# BSD 3-Clause License
# 
# Copyright 2020 Lawrence T. Clark, Vinay Vashishtha, or Arizona State
# University
# 
# Redistribution and use in source and binary forms, with or without
# modification, are permitted provided that the following conditions are met:
# 
# 1. Redistributions of source code must retain the above copyright notice,
# this list of conditions and the following disclaimer.
# 
# 2. Redistributions in binary form must reproduce the above copyright
# notice, this list of conditions and the following disclaimer in the
# documentation and/or other materials provided with the distribution.
# 
# 3. Neither the name of the copyright holder nor the names of its
# contributors may be used to endorse or promote products derived from this
# software without specific prior written permission.
# 
# THIS SOFTWARE IS PROVIDED BY THE COPYRIGHT HOLDERS AND CONTRIBUTORS "AS IS"
# AND ANY EXPRESS OR IMPLIED WARRANTIES, INCLUDING, BUT NOT LIMITED TO, THE
# IMPLIED WARRANTIES OF MERCHANTABILITY AND FITNESS FOR A PARTICULAR PURPOSE
# ARE DISCLAIMED. IN NO EVENT SHALL THE COPYRIGHT HOLDER OR CONTRIBUTORS BE
# LIABLE FOR ANY DIRECT, INDIRECT, INCIDENTAL, SPECIAL, EXEMPLARY, OR
# CONSEQUENTIAL DAMAGES (INCLUDING, BUT NOT LIMITED TO, PROCUREMENT OF
# SUBSTITUTE GOODS OR SERVICES; LOSS OF USE, DATA, OR PROFITS; OR BUSINESS
# INTERRUPTION) HOWEVER CAUSED AND ON ANY THEORY OF LIABILITY, WHETHER IN
# CONTRACT, STRICT LIABILITY, OR TORT (INCLUDING NEGLIGENCE OR OTHERWISE)
# ARISING IN ANY WAY OUT OF THE USE OF THIS SOFTWARE, EVEN IF ADVISED OF THE
# POSSIBILITY OF SUCH DAMAGE.

# -----------------------------------------------------------------------------
# smic-n3 variant of the ASAP7 technology LEF.
# Author of the variant: Simone Machetti
#
# The ASAP7 standard cells draw their pins and wiring on M1 and M2 only, so
# everything up to and including V2 is ASAP7's, unchanged. From M3 up the stack
# takes the metal pitches measured on SMIC N+3 (Kirin 9030 Pro teardown), with
# widths at half the pitch and the preferred directions alternating as before:
#
#   M1, M2      36 nm   ASAP7, frozen by the cells
#   M3          44 nm   fine layer, ASAP7's M3 rules scaled by 44/36
#   M4 to M6    80 nm   classic rules, ASAP7's M8 verbatim
#   M7 to M10  128 nm   classic rules, ASAP7's M8 scaled by 1.6
#   M11        148 nm   classic rules, ASAP7's M8 scaled by 1.85
#   Pad                 ASAP7's, unused
#
# The pitches are measurements; the design rules around them are not published
# and are ASAP7's own, scaled. This file holds no thickness or material data:
# the electrical model is in setRC.tcl and rcx_patterns.rules.
# -----------------------------------------------------------------------------

VERSION 5.8 ;
BUSBITCHARS "[]" ;
DIVIDERCHAR "/" ;
CLEARANCEMEASURE EUCLIDEAN ;
USEMINSPACING OBS OFF ;

UNITS
 DATABASE MICRONS 1000 ;
END UNITS
 MANUFACTURINGGRID 0.001 ;

PROPERTYDEFINITIONS
  LAYER LEF58_TYPE STRING ;
  LAYER LEF58_PITCH STRING ;
  LAYER LEF58_GAP STRING ;
  LAYER LEF58_EOLKEEPOUT STRING ;
  LAYER LEF58_SPACING STRING ;
  LAYER LEF58_CORNERSPACING STRING ;
  LAYER LEF58_WIDTHTABLE STRING ;
  LAYER LEF58_CUTCLASS STRING ;
  LAYER LEF58_SPACINGTABLE STRING ;
  LAYER LEF58_ENCLOSURE STRING ;
  LAYER LEF58_RIGHTWAYONGRIDONLY STRING ;
  LAYER LEF58_RECTONLY STRING ;
END PROPERTYDEFINITIONS

#LAYER OVERLAP
#  TYPE OVERLAP ;
#END OVERLAP
#

LAYER LVTN
  TYPE IMPLANT ;
END LVTN

LAYER LVTP
  TYPE IMPLANT ;
END LVTP

LAYER RVTN
  TYPE IMPLANT ;
END RVTN

LAYER RVTP
  TYPE IMPLANT ;
END RVTP

LAYER SLVTN
  TYPE IMPLANT ;
END SLVTN

LAYER SLVTP
  TYPE IMPLANT ;
END SLVTP

LAYER nwell
  TYPE MASTERSLICE ;
 PROPERTY LEF58_TYPE "TYPE NWELL ;" ;
END nwell

LAYER pwell
  TYPE MASTERSLICE ;
 PROPERTY LEF58_TYPE "TYPE PWELL ;" ;
END pwell

LAYER Gate
  TYPE MASTERSLICE ;
END Gate

LAYER Active
  TYPE MASTERSLICE ;
END Active

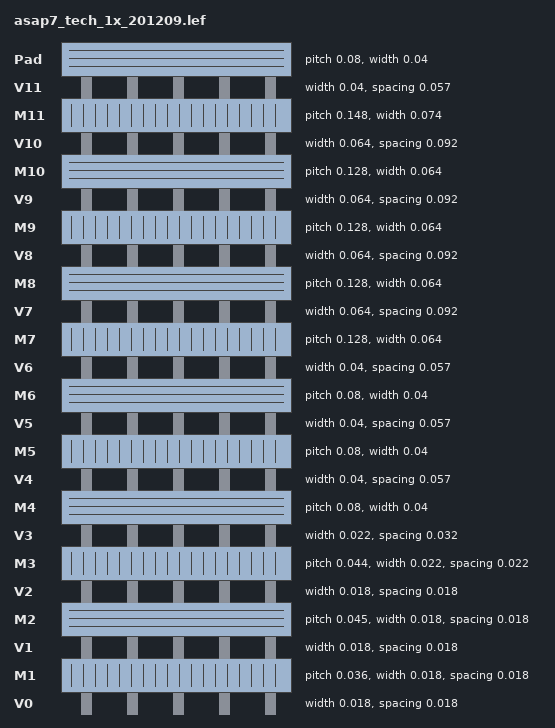
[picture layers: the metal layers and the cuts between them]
LAYER V0
  TYPE CUT ;
 SPACING 0.018 ;
 WIDTH 0.018 ;
END V0

LAYER M1
  TYPE ROUTING ;
  DIRECTION VERTICAL ;
 PITCH 0.036 ;
 WIDTH 0.018 ;
 SPACING 0.018 ;
 AREA 0.000666 ; # Min Area
                                    # we only allow landing on pins (set in router) so area should not matter
 SPACING 0.018 RANGE 0.036 1.0 ; # This rule is redundant with the SPACING rule

 PROPERTY LEF58_EOLKEEPOUT "EOLKEEPOUT 0.01825 EXTENSION 0.0 0.0 0.031 ;" ; # Tip to Tip Spacing

 PROPERTY LEF58_CORNERSPACING "CORNERSPACING CONVEXCORNER CORNERONLY 0.01 WIDTH 0.018 SPACING 0.018 ;" ;
 OFFSET 0.0 ;

END M1

LAYER V1
  TYPE CUT ;
 SPACING 0.018 ; # unlike generate, this is really spacing, not center to center.
 WIDTH 0.018 ;
END V1

LAYER M2
  TYPE ROUTING ;
  DIRECTION HORIZONTAL ;
 WIDTH 0.018 ; # Min Width
 SPACING 0.018 ; # Min Spacing

 OFFSET -0.27 ;

  #  MINSIZE is set so that the minimum lenght of a segment is 36nm. At the proper rule size of
  #  31nm, the lines can't be minimum space. This causes DRCs (like crazy). Same for M3
  #  MINSIZE 0.112 0.072 ; 
  # area is adjusted to match this (Nanoroute requires both AREA and MINSIZE)

 AREA 0.000666 ;
 MINSIZE 0.037 0.018 ;

 PITCH 0.045 0.036 ;

  # this enforces the correct routing tracks on M2 with wide M2 power rails

 PROPERTY LEF58_PITCH "
 PITCH 0.036 FIRSTLASTPITCH 0.045
   ;
 " ;

  # this checks for distance in any direction so is not correct
  # 0.070 is to avoid conflicts with the adjacent lines. This should be caught by CORNERSPACING below
  #   SPACING 0.124 ENDOFLINE 0.1 WITHIN 0.070 ;

 PROPERTY LEF58_SPACING
 " SPACING 0.018 ENDOFLINE 0.025 WITHIN 0.02 ENDTOEND 0.031
 PARALLELEDGE 0.025 WITHIN 0.02 ; " ;

 PROPERTY LEF58_EOLKEEPOUT "
 EOLKEEPOUT 0.025 EXTENSION 0.0 0.0125 0.031 CORNERONLY ;
 " ;

 PROPERTY LEF58_CORNERSPACING "
 CORNERSPACING CONVEXCORNER WIDTH 0.0 SPACING 0.02 ;
 " ; # CORNER to CORNER SPACING Rule

  # Originally no width table for M2 since it is the follow rails. 
  # They can be 1x or 2x (2x causes DRCs on SAV V1). However, this seems to allow a double width M2
  # on vias, which violates. Thus, this is added. Note that wide power follow rails will violate.

 PROPERTY LEF58_WIDTHTABLE "
 WIDTHTABLE 0.018 0.09 0.162 0.234 0.306 0.378 ;
 " ;

 PROPERTY LEF58_RIGHTWAYONGRIDONLY "
      RIGHTWAYONGRIDONLY ;
 " ;

 PROPERTY LEF58_RECTONLY "
      RECTONLY ;
 " ;

END M2

LAYER V2
  TYPE CUT ;
 SPACING 0.018 ;
 WIDTH 0.018 ;
END V2

LAYER M3
  TYPE ROUTING ;
  DIRECTION VERTICAL ;
 PITCH 0.044 ;
 OFFSET 0.0 ;
 WIDTH 0.022 ; # Min Width
 SPACING 0.022 ; # Min Spacing

  # smic-n3: the last finely patterned layer. It keeps ASAP7's M3 rule set, with
  # every length scaled by the pitch ratio 44/36 and rounded to the 1 nm grid.
  # MINSIZE keeps the minimum segment one nanometre above the pitch, as on M2.

 AREA 0.00099 ;
 MINSIZE 0.045 0.022 ;

 PROPERTY LEF58_SPACING
 " SPACING 0.022 ENDOFLINE 0.031 WITHIN 0.015 ENDTOEND 0.038
 PARALLELEDGE 0.031 WITHIN 0.024 ; " ;

 PROPERTY LEF58_EOLKEEPOUT "
 EOLKEEPOUT 0.031 EXTENSION 0.0 0.015 0.038 CORNERONLY ;
 " ;

 PROPERTY LEF58_CORNERSPACING "
 CORNERSPACING CONVEXCORNER WIDTH 0.0 SPACING 0.024
   ;
 " ; # CORNER to CORNER SPACING Rule

  # special route widths are integer numbers of tracks: 1, 5, 9, 13... min widths

 PROPERTY LEF58_WIDTHTABLE
 " WIDTHTABLE 0.022 0.11 0.198 0.286 0.374 0.462 ; " ;

 PROPERTY LEF58_RIGHTWAYONGRIDONLY "
      RIGHTWAYONGRIDONLY ;
 " ;

 PROPERTY LEF58_RECTONLY "
      RECTONLY ;
 " ;

END M3

# smic-n3: from here up every layer is coarse and single-patterned, and carries
# the classic rule set of ASAP7's M8: pitch, width, minimum area, a spacing table
# by parallel run length, minimum cut, maximum width and minimum step. The 80 nm
# layers (M4 to M6) are ASAP7's M8 verbatim; the 128 nm layers (M7 to M10) and
# the 148 nm layer (M11) are the same block with every length scaled by the
# width ratio (1.6 and 1.85) and the area by its square. Cut layers are square
# at the width of the narrower neighbour, spaced as ASAP7 spaces V7 and V8
# (1.43 x the cut).

LAYER V3
  TYPE CUT ;
 SPACING 0.032 ;
 WIDTH 0.022 ;
END V3

LAYER M4
  TYPE ROUTING ;
  DIRECTION HORIZONTAL ;
 PITCH 0.08 0.08 ;
 WIDTH 0.04 ;
 AREA 0.00752 ;

  SPACINGTABLE
 PARALLELRUNLENGTH 0.0 0.39975 1.19975 1.79975
 WIDTH 0.0 0.04 0.04 0.04 0.04
 WIDTH 0.05975 0.04 0.04 0.04 0.04
 WIDTH 0.07975 0.04 0.04 0.04 0.04
 WIDTH 0.11975 0.04 0.04 0.04 0.04
 WIDTH 0.49975 0.04 0.04 0.04 0.5
 WIDTH 0.99975 0.04 0.04 0.04 1.0 ;

 MINIMUMCUT 2 WIDTH 1.805 WITHIN 1.705 FROMBELOW ;
 MINIMUMCUT 2 WIDTH 1.805 WITHIN 1.705 FROMABOVE ;
 MAXWIDTH 2.0 ;
 MINSTEP 0.04 STEP ;
END M4

LAYER V4
  TYPE CUT ;
 SPACING 0.057 ;
 WIDTH 0.04 ;
END V4

LAYER M5
  TYPE ROUTING ;
  DIRECTION VERTICAL ;
 PITCH 0.08 0.08 ;
 WIDTH 0.04 ;
 AREA 0.00752 ;

  SPACINGTABLE
 PARALLELRUNLENGTH 0.0 0.39975 1.19975 1.79975
 WIDTH 0.0 0.04 0.04 0.04 0.04
 WIDTH 0.05975 0.04 0.04 0.04 0.04
 WIDTH 0.07975 0.04 0.04 0.04 0.04
 WIDTH 0.11975 0.04 0.04 0.04 0.04
 WIDTH 0.49975 0.04 0.04 0.04 0.5
 WIDTH 0.99975 0.04 0.04 0.04 1.0 ;

 MINIMUMCUT 2 WIDTH 1.805 WITHIN 1.705 FROMBELOW ;
 MINIMUMCUT 2 WIDTH 1.805 WITHIN 1.705 FROMABOVE ;
 MAXWIDTH 2.0 ;
 MINSTEP 0.04 STEP ;
END M5

LAYER V5
  TYPE CUT ;
 SPACING 0.057 ;
 WIDTH 0.04 ;
END V5

LAYER M6
  TYPE ROUTING ;
  DIRECTION HORIZONTAL ;
 PITCH 0.08 0.08 ;
 WIDTH 0.04 ;
 AREA 0.00752 ;

  SPACINGTABLE
 PARALLELRUNLENGTH 0.0 0.39975 1.19975 1.79975
 WIDTH 0.0 0.04 0.04 0.04 0.04
 WIDTH 0.05975 0.04 0.04 0.04 0.04
 WIDTH 0.07975 0.04 0.04 0.04 0.04
 WIDTH 0.11975 0.04 0.04 0.04 0.04
 WIDTH 0.49975 0.04 0.04 0.04 0.5
 WIDTH 0.99975 0.04 0.04 0.04 1.0 ;

 MINIMUMCUT 2 WIDTH 1.805 WITHIN 1.705 FROMBELOW ;
 MINIMUMCUT 2 WIDTH 1.805 WITHIN 1.705 FROMABOVE ;
 MAXWIDTH 2.0 ;
 MINSTEP 0.04 STEP ;
END M6

LAYER V6
  TYPE CUT ;
 SPACING 0.057 ;
 WIDTH 0.04 ;
END V6

LAYER M7
  TYPE ROUTING ;
  DIRECTION VERTICAL ;
 PITCH 0.128 0.128 ;
 WIDTH 0.064 ;
 AREA 0.01925 ;

  SPACINGTABLE
 PARALLELRUNLENGTH 0.0 0.63975 1.91975 2.87975
 WIDTH 0.0 0.064 0.064 0.064 0.064
 WIDTH 0.09575 0.064 0.064 0.064 0.064
 WIDTH 0.12775 0.064 0.064 0.064 0.064
 WIDTH 0.19175 0.064 0.064 0.064 0.064
 WIDTH 0.79975 0.064 0.064 0.064 0.8
 WIDTH 1.59975 0.064 0.064 0.064 1.6 ;

 MINIMUMCUT 2 WIDTH 2.888 WITHIN 2.728 FROMBELOW ;
 MINIMUMCUT 2 WIDTH 2.888 WITHIN 2.728 FROMABOVE ;
 MAXWIDTH 3.2 ;
 MINSTEP 0.064 STEP ;
END M7

LAYER V7
  TYPE CUT ;
 SPACING 0.092 ;
 WIDTH 0.064 ;
END V7

LAYER M8
  TYPE ROUTING ;
  DIRECTION HORIZONTAL ;
 PITCH 0.128 0.128 ;
 WIDTH 0.064 ;
 AREA 0.01925 ;

  SPACINGTABLE
 PARALLELRUNLENGTH 0.0 0.63975 1.91975 2.87975
 WIDTH 0.0 0.064 0.064 0.064 0.064
 WIDTH 0.09575 0.064 0.064 0.064 0.064
 WIDTH 0.12775 0.064 0.064 0.064 0.064
 WIDTH 0.19175 0.064 0.064 0.064 0.064
 WIDTH 0.79975 0.064 0.064 0.064 0.8
 WIDTH 1.59975 0.064 0.064 0.064 1.6 ;

 MINIMUMCUT 2 WIDTH 2.888 WITHIN 2.728 FROMBELOW ;
 MINIMUMCUT 2 WIDTH 2.888 WITHIN 2.728 FROMABOVE ;
 MAXWIDTH 3.2 ;
 MINSTEP 0.064 STEP ;
END M8

LAYER V8
  TYPE CUT ;
 SPACING 0.092 ;
 WIDTH 0.064 ;
END V8

LAYER M9
  TYPE ROUTING ;
  DIRECTION VERTICAL ;
 PITCH 0.128 0.128 ;
 WIDTH 0.064 ;
 AREA 0.01925 ;

  SPACINGTABLE
 PARALLELRUNLENGTH 0.0 0.63975 1.91975 2.87975
 WIDTH 0.0 0.064 0.064 0.064 0.064
 WIDTH 0.09575 0.064 0.064 0.064 0.064
 WIDTH 0.12775 0.064 0.064 0.064 0.064
 WIDTH 0.19175 0.064 0.064 0.064 0.064
 WIDTH 0.79975 0.064 0.064 0.064 0.8
 WIDTH 1.59975 0.064 0.064 0.064 1.6 ;

 MINIMUMCUT 2 WIDTH 2.888 WITHIN 2.728 FROMBELOW ;
 MINIMUMCUT 2 WIDTH 2.888 WITHIN 2.728 FROMABOVE ;
 MAXWIDTH 3.2 ;
 MINSTEP 0.064 STEP ;
END M9

LAYER V9
  TYPE CUT ;
 SPACING 0.092 ;
 WIDTH 0.064 ;
END V9

LAYER M10
  TYPE ROUTING ;
  DIRECTION HORIZONTAL ;
 PITCH 0.128 0.128 ;
 WIDTH 0.064 ;
 AREA 0.01925 ;

  SPACINGTABLE
 PARALLELRUNLENGTH 0.0 0.63975 1.91975 2.87975
 WIDTH 0.0 0.064 0.064 0.064 0.064
 WIDTH 0.09575 0.064 0.064 0.064 0.064
 WIDTH 0.12775 0.064 0.064 0.064 0.064
 WIDTH 0.19175 0.064 0.064 0.064 0.064
 WIDTH 0.79975 0.064 0.064 0.064 0.8
 WIDTH 1.59975 0.064 0.064 0.064 1.6 ;

 MINIMUMCUT 2 WIDTH 2.888 WITHIN 2.728 FROMBELOW ;
 MINIMUMCUT 2 WIDTH 2.888 WITHIN 2.728 FROMABOVE ;
 MAXWIDTH 3.2 ;
 MINSTEP 0.064 STEP ;
END M10

LAYER V10
  TYPE CUT ;
 SPACING 0.092 ;
 WIDTH 0.064 ;
END V10

LAYER M11
  TYPE ROUTING ;
  DIRECTION VERTICAL ;
 PITCH 0.148 0.148 ;
 WIDTH 0.074 ;
 AREA 0.02574 ;

  SPACINGTABLE
 PARALLELRUNLENGTH 0.0 0.73975 2.21975 3.32975
 WIDTH 0.0 0.074 0.074 0.074 0.074
 WIDTH 0.11075 0.074 0.074 0.074 0.074
 WIDTH 0.14775 0.074 0.074 0.074 0.074
 WIDTH 0.22175 0.074 0.074 0.074 0.074
 WIDTH 0.92475 0.074 0.074 0.074 0.925
 WIDTH 1.84975 0.074 0.074 0.074 1.85 ;

 MINIMUMCUT 2 WIDTH 3.339 WITHIN 3.154 FROMBELOW ;
 MINIMUMCUT 2 WIDTH 3.339 WITHIN 3.154 FROMABOVE ;
 MAXWIDTH 3.7 ;
 MINSTEP 0.074 STEP ;
END M11

# smic-n3: the Pad layer and its cut are ASAP7's, moved above M11. Nothing in the
# flow routes on them. SMIC's two package-scale layers above M11 are left out.

LAYER V11
  TYPE CUT ;
 SPACING 0.057 ;
 WIDTH 0.04 ;
END V11

LAYER Pad
  TYPE ROUTING ;
  DIRECTION HORIZONTAL ;
 PITCH 0.08 0.08 ;
 WIDTH 0.04 ;
  SPACINGTABLE
 PARALLELRUNLENGTH 0.0 11.99975
 WIDTH 0.0 2.0 2.0
 WIDTH 11.99975 2.0 3.0 ;
 MINIMUMCUT 1 WIDTH 0.04 WITHIN 1.705 FROMBELOW ;
 MINIMUMCUT 1 WIDTH 0.36 WITHIN 1.705 FROMBELOW ;
 MINIMUMCUT 2 WIDTH 1.805 WITHIN 1.705 FROMBELOW ;
 MINIMUMDENSITY 20.0 ;
 MAXIMUMDENSITY 80.0 ;
 DENSITYCHECKWINDOW 100.0 100.0 ;
 DENSITYCHECKSTEP 50.0 ;
END Pad

# vias
#
# smic-n3: one fixed via per adjacent pair, used as the router's default cut.
# On the coarse layers the metal is a square of the wire width around the cut,
# as in ASAP7's VIA89. On M3 the enclosure runs 5 nm past the cut along the wire,
# as in ASAP7's VIA23 and VIA34.

VIA VIA11Pad Default
  LAYER M11 ;
 RECT -0.05 -0.05 0.05 0.05 ;
  LAYER Pad ;
 RECT -0.05 -0.05 0.05 0.05 ;
  LAYER V11 ;
 RECT -0.05 -0.05 0.05 0.05 ;
END VIA11Pad

VIA VIA1011 Default
  LAYER M10 ;
 RECT -0.032 -0.032 0.032 0.032 ;
  LAYER M11 ;
 RECT -0.037 -0.037 0.037 0.037 ;
  LAYER V10 ;
 RECT -0.032 -0.032 0.032 0.032 ;
END VIA1011

VIA VIA910 Default
  LAYER M9 ;
 RECT -0.032 -0.032 0.032 0.032 ;
  LAYER M10 ;
 RECT -0.032 -0.032 0.032 0.032 ;
  LAYER V9 ;
 RECT -0.032 -0.032 0.032 0.032 ;
END VIA910

VIA VIA89 Default
  LAYER M8 ;
 RECT -0.032 -0.032 0.032 0.032 ;
  LAYER M9 ;
 RECT -0.032 -0.032 0.032 0.032 ;
  LAYER V8 ;
 RECT -0.032 -0.032 0.032 0.032 ;
END VIA89

VIA VIA78 Default
  LAYER M7 ;
 RECT -0.032 -0.032 0.032 0.032 ;
  LAYER M8 ;
 RECT -0.032 -0.032 0.032 0.032 ;
  LAYER V7 ;
 RECT -0.032 -0.032 0.032 0.032 ;
END VIA78

VIA VIA67 Default
  LAYER M6 ;
 RECT -0.02 -0.02 0.02 0.02 ;
  LAYER M7 ;
 RECT -0.032 -0.032 0.032 0.032 ;
  LAYER V6 ;
 RECT -0.02 -0.02 0.02 0.02 ;
END VIA67

VIA VIA56 Default
  LAYER M5 ;
 RECT -0.02 -0.02 0.02 0.02 ;
  LAYER M6 ;
 RECT -0.02 -0.02 0.02 0.02 ;
  LAYER V5 ;
 RECT -0.02 -0.02 0.02 0.02 ;
END VIA56

VIA VIA45 Default
  LAYER M4 ;
 RECT -0.02 -0.02 0.02 0.02 ;
  LAYER M5 ;
 RECT -0.02 -0.02 0.02 0.02 ;
  LAYER V4 ;
 RECT -0.02 -0.02 0.02 0.02 ;
END VIA45

VIA VIA34 Default
  LAYER M3 ;
 RECT -0.011 -0.016 0.011 0.016 ;
  LAYER M4 ;
 RECT -0.02 -0.02 0.02 0.02 ;
  LAYER V3 ;
 RECT -0.011 -0.011 0.011 0.011 ;
END VIA34

VIA VIA23 Default
  LAYER M2 ;
 RECT -0.014 -0.009 0.014 0.009 ;
  LAYER M3 ;
 RECT -0.011 -0.014 0.011 0.014 ;
  LAYER V2 ;
 RECT -0.009 -0.009 0.009 0.009 ;
END VIA23

VIA VIA12 Default
  LAYER M1 ;
 RECT -0.009 -0.011 0.009 0.011 ;
  LAYER M2 ;
 RECT -0.014 -0.009 0.014 0.009 ;
  LAYER V1 ;
 RECT -0.009 -0.009 0.009 0.009 ;
END VIA12

#################################
### VIARULE GENERATE DEFAULTS ###
#################################
#
# smic-n3: one generate rule per adjacent pair of coarse layers, which is what the
# power grid builds its via arrays from. SPACING is centre to centre: the cut
# plus the cut-layer spacing. Between M2 and M3 the arrays are built from the
# fixed via above, as in ASAP7. ASAP7's wide power rules are dropped, since they
# are tied to its strap widths.

VIARULE Pad_M11 GENERATE DEFAULT
  LAYER M11 ;
 ENCLOSURE 0.0 0.0 ;
  LAYER Pad ;
 ENCLOSURE 0.011 0.0 ;
  LAYER V11 ;
 RECT -0.02 -0.02 0.02 0.02 ;
 SPACING 0.097 BY 0.097 ;
END Pad_M11

VIARULE M11_M10 GENERATE DEFAULT
  LAYER M10 ;
 ENCLOSURE 0.0 0.0 ;
  LAYER M11 ;
 ENCLOSURE 0.005 0.005 ;
  LAYER V10 ;
 RECT -0.032 -0.032 0.032 0.032 ;
 SPACING 0.156 BY 0.156 ;
END M11_M10

VIARULE M10_M9 GENERATE DEFAULT
  LAYER M9 ;
 ENCLOSURE 0.0 0.0 ;
  LAYER M10 ;
 ENCLOSURE 0.0 0.0 ;
  LAYER V9 ;
 RECT -0.032 -0.032 0.032 0.032 ;
 SPACING 0.156 BY 0.156 ;
END M10_M9

VIARULE M9_M8 GENERATE DEFAULT
  LAYER M8 ;
 ENCLOSURE 0.0 0.0 ;
  LAYER M9 ;
 ENCLOSURE 0.0 0.0 ;
  LAYER V8 ;
 RECT -0.032 -0.032 0.032 0.032 ;
 SPACING 0.156 BY 0.156 ;
END M9_M8

VIARULE M8_M7 GENERATE DEFAULT
  LAYER M7 ;
 ENCLOSURE 0.0 0.0 ;
  LAYER M8 ;
 ENCLOSURE 0.0 0.0 ;
  LAYER V7 ;
 RECT -0.032 -0.032 0.032 0.032 ;
 SPACING 0.156 BY 0.156 ;
END M8_M7

VIARULE M7_M6 GENERATE DEFAULT
  LAYER M6 ;
 ENCLOSURE 0.0 0.0 ;
  LAYER M7 ;
 ENCLOSURE 0.012 0.012 ;
  LAYER V6 ;
 RECT -0.02 -0.02 0.02 0.02 ;
 SPACING 0.097 BY 0.097 ;
END M7_M6

VIARULE M6_M5 GENERATE DEFAULT
  LAYER M5 ;
 ENCLOSURE 0.0 0.0 ;
  LAYER M6 ;
 ENCLOSURE 0.0 0.0 ;
  LAYER V5 ;
 RECT -0.02 -0.02 0.02 0.02 ;
 SPACING 0.097 BY 0.097 ;
END M6_M5

VIARULE M5_M4 GENERATE DEFAULT
  LAYER M4 ;
 ENCLOSURE 0.0 0.0 ;
  LAYER M5 ;
 ENCLOSURE 0.0 0.0 ;
  LAYER V4 ;
 RECT -0.02 -0.02 0.02 0.02 ;
 SPACING 0.097 BY 0.097 ;
END M5_M4

# M3 to M4: M3 runs 5 nm past the cut along the wire, as ASAP7's V3 asks of M3,
# and M4 covers the cut with its full width. The power grid also sizes the M3
# patch of a via stack through M3 from this enclosure.

VIARULE M4_M3 GENERATE DEFAULT
  LAYER M3 ;
 ENCLOSURE 0.0 0.005 ;
  LAYER M4 ;
 ENCLOSURE 0.009 0.009 ;
  LAYER V3 ;
 RECT -0.011 -0.011 0.011 0.011 ;
 SPACING 0.054 BY 0.054 ;
END M4_M3

VIARULE M2_M1 GENERATE DEFAULT
  LAYER M1 ;
 ENCLOSURE 0.0 0.0 ;
  LAYER M2 ;
 ENCLOSURE 0.002 0.0 ;
  LAYER V1 ;
 RECT -0.009 -0.009 0.009 0.009 ;
 SPACING 0.036 BY 0.036 ;
END M2_M1

END LIBRARY
